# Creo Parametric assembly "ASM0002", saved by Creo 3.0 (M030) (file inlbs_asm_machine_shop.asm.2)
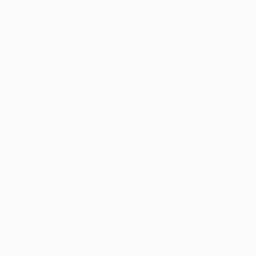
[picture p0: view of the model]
Units: Inch lbm Second (Pro/E Default); INCH, POUND, SECS

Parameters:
  YOUR_INITIAL = "XX"
  MATERIAL = "N/A"
  TEAM_NAME = "XXX XXX"
  FINISH = "N/A"

Created from: INLBS_ASM_DESIGN.ASM

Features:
  1. datum plane "ASM_RIGHT"
  2. datum plane "ASM_TOP"
  3. datum plane "ASM_FRONT"
  4. coordinate system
